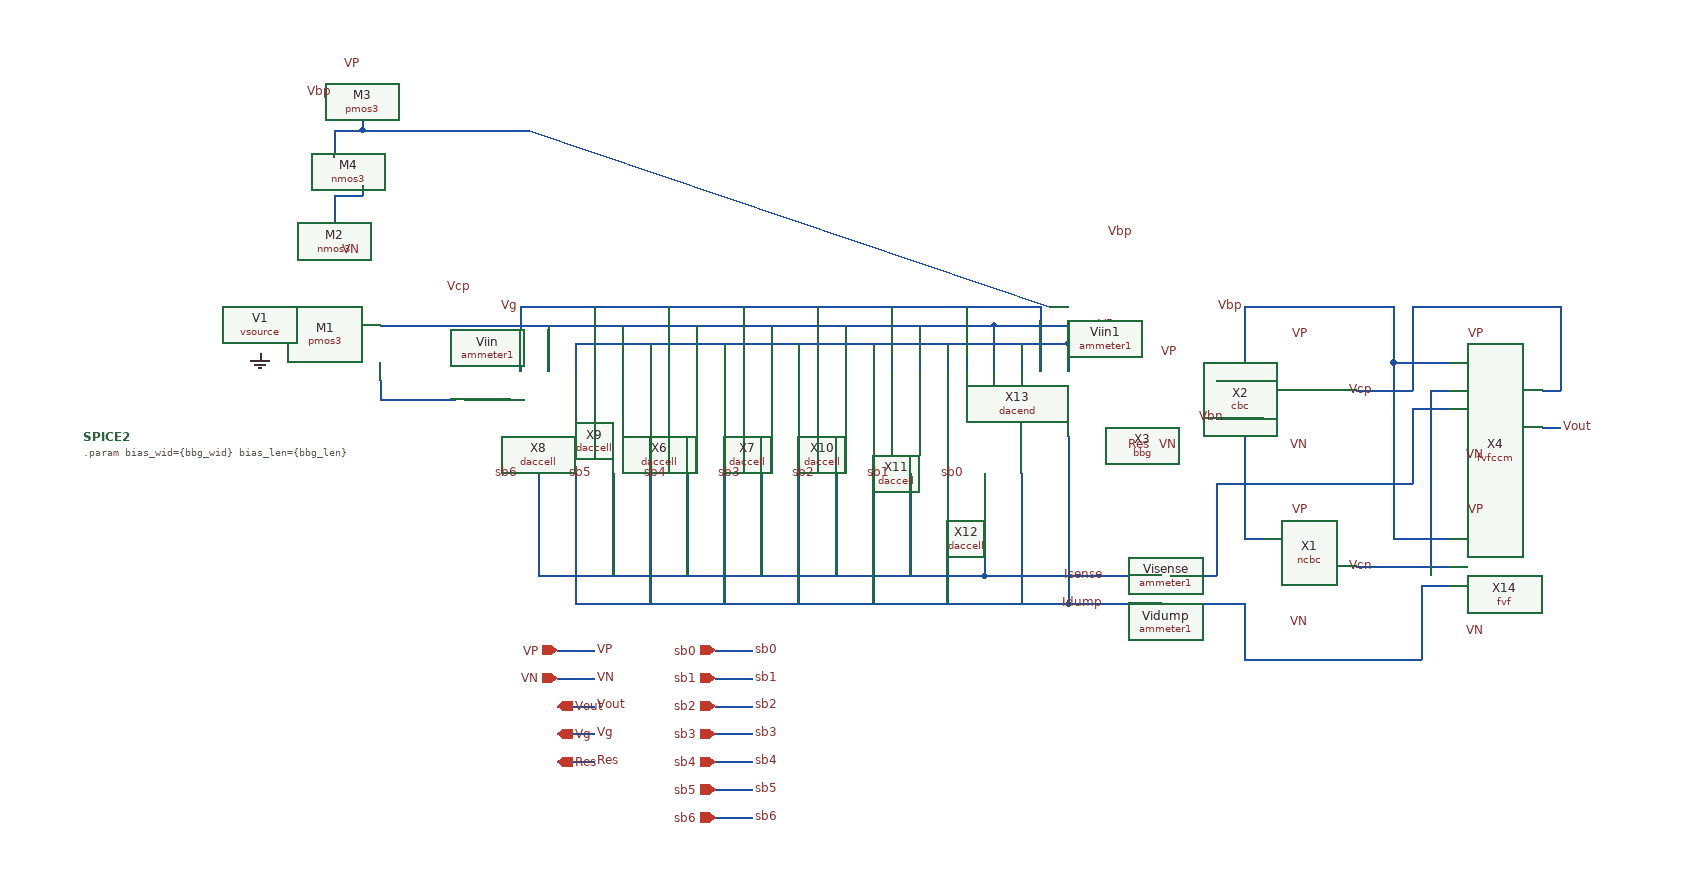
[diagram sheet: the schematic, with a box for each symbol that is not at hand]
v {xschem version=3.4.8RC file_version=1.3}
G {}
K {}
V {}
S {}
F {}
E {}
N 450 -420 600 -420 {lab=Vbp}
N 600 -420 600 -360 {lab=Vbp}
N 600 -360 640 -360 {lab=Vbp}
N 640 -360 650 -360 {lab=Vbp}
N 650 -360 660 -360 {lab=Vbp}
N 760 -290 780 -290 {lab=Vout}
N 220 -420 220 -350 {lab=Vg}
N 140 -420 140 -350 {lab=Vg}
N 60 -420 60 -350 {lab=Vg}
N -20 -420 -20 -350 {lab=Vg}
N -100 -420 -100 -350 {lab=Vg}
N -180 -420 -180 -350 {lab=Vg}
N -260 -420 -260 -350 {lab=Vg}
N -340 -420 -340 -350 {lab=Vg}
N -340 -420 220 -420 {lab=Vg}
N -490 -340 -490 -320 {lab=#net1}
N 160 -240 160 -130 {lab=Isense}
N 200 -240 200 -100 {lab=Idump}
N 80 -240 80 -130 {lab=Isense}
N 120 -240 120 -100 {lab=Idump}
N 0 -240 0 -130 {lab=Isense}
N 40 -240 40 -100 {lab=Idump}
N -80 -240 -80 -130 {lab=Isense}
N -40 -240 -40 -100 {lab=Idump}
N -160 -240 -160 -130 {lab=Isense}
N -120 -240 -120 -100 {lab=Idump}
N -240 -240 -240 -130 {lab=Isense}
N -200 -240 -200 -100 {lab=Idump}
N -320 -240 -320 -130 {lab=Isense}
N -280 -240 -280 -100 {lab=Idump}
N 250 -280 250 -100 {lab=Idump}
N -280 -100 250 -100 {lab=Idump}
N -320 -130 160 -130 {lab=Isense}
N -390 -320 -350 -320 {lab=#net2}
N 250 -100 260 -100 {lab=Idump}
N 160 -130 290 -130 {lab=Isense}
N 440 -170 460 -170 {lab=Vbp}
N 560 -330 580 -330 {lab=Vcp}
N 760 -330 780 -330 {lab=Vcp}
N 640 -330 660 -330 {lab=Vcn}
N -400 -320 -390 -320 {lab=#net2}
N 170 -400 170 -350 {lab=VP}
N 90 -400 90 -350 {lab=VP}
N 10 -400 10 -350 {lab=VP}
N -70 -400 -70 -350 {lab=VP}
N -150 -400 -150 -350 {lab=VP}
N -230 -400 -230 -350 {lab=VP}
N -310 -400 -310 -350 {lab=VP}
N -380 -400 170 -400 {lab=VP}
N -490 -400 -380 -400 {lab=VP}
N -280 -380 -280 -350 {lab=VN}
N -200 -380 -200 -350 {lab=VN}
N -120 -380 -120 -350 {lab=VN}
N -40 -380 -40 -350 {lab=VN}
N 40 -380 40 -350 {lab=VN}
N 120 -380 120 -350 {lab=VN}
N 200 -380 200 -350 {lab=VN}
N 250 -380 250 -350 {lab=VN}
N -280 -380 250 -380 {lab=VN}
N 250 -380 280 -380 {lab=VN}
N 440 -340 440 -170 {lab=Vbp}
N 440 -420 440 -340 {lab=Vbp}
N 440 -420 450 -420 {lab=Vbp}
N 410 -300 460 -300 {lab=Vbn}
N 410 -340 440 -340 {lab=Vbp}
N 600 -170 650 -170 {lab=Vbp}
N 600 -360 600 -170 {lab=Vbp}
N 630 -120 660 -120 {lab=#net3}
N 650 -170 660 -170 {lab=Vbp}
N 780 -420 780 -330 {lab=Vcp}
N 620 -420 780 -420 {lab=Vcp}
N 620 -420 620 -330 {lab=Vcp}
N 580 -330 620 -330 {lab=Vcp}
N 640 -330 640 -140 {lab=Vcn}
N 620 -310 660 -310 {lab=#net4}
N 440 -100 440 -40 {lab=#net3}
N 440 -40 630 -40 {lab=#net3}
N 630 -120 630 -40 {lab=#net3}
N 620 -310 620 -230 {lab=#net4}
N 410 -230 620 -230 {lab=#net4}
N 410 -230 410 -130 {lab=#net4}
N 170 -400 280 -400 {lab=VP}
N -130 -50 -90 -50 {lab=sb0}
N -300 10 -260 10 {lab=Vout}
N -270 -20 -260 -20 {lab=VN}
N -300 -20 -270 -20 {lab=VN}
N -300 -50 -260 -50 {lab=VP}
N -300 40 -260 40 {lab=Vg}
N -130 -20 -90 -20 {lab=sb1}
N -130 10 -90 10 {lab=sb2}
N -130 40 -90 40 {lab=sb3}
N -130 70 -90 70 {lab=sb4}
N -130 100 -90 100 {lab=sb5}
N -130 130 -90 130 {lab=sb6}
N -300 70 -260 70 {lab=Res}
N 580 -140 660 -140 {lab=Vcn}
N 560 -140 580 -140 {lab=Vcn}
N 290 -130 350 -130 {lab=Isense}
N 360 -130 410 -130 {lab=#net4}
N 260 -100 350 -100 {lab=Idump}
N 360 -100 440 -100 {lab=#net3}
N -490 -320 -410 -320 {lab=#net1}
N -540 -610 -540 -580 {lab=#net5}
N -540 -610 -510 -610 {lab=#net5}
N -510 -550 -510 -540 {lab=#net6}
N -510 -620 -510 -610 {lab=#net5}
N -510 -610 -330 -610 {lab=#net5}
N -330 -610 230 -420 {lab=#net5}
N -540 -540 -540 -510 {lab=#net6}
N -540 -540 -510 -540 {lab=#net6}
C {cbc.sym} 460 -270 0 0 {name=X2}
C {bbg.sym} 330 -270 0 0 {name=X3}
C {fvfccm.sym} 670 -260 0 0 {name=X4}
C {lab_pin.sym} 580 -330 1 0 {name=p3 sig_type=std_logic lab=Vcp}
C {lab_pin.sym} 420 -300 3 0 {name=p5 sig_type=std_logic lab=Vbn}
C {daccell.sym} -190 -240 0 0 {name=X6}
C {daccell.sym} -110 -240 0 0 {name=X7}
C {daccell.sym} -350 -240 0 0 {name=X8}
C {daccell.sym} -270 -240 0 0 {name=X9}
C {daccell.sym} -30 -240 0 0 {name=X10}
C {daccell.sym} 50 -240 0 0 {name=X11}
C {daccell.sym} 130 -240 0 0 {name=X12}
C {dacend.sym} 210 -280 0 0 {name=X13}
C {lab_pin.sym} -520 -370 0 0 {name=p20 sig_type=std_logic lab=Vbp}
C {fvf.sym} 660 -70 0 0 {name=X14}
C {lab_pin.sym} 290 -130 1 0 {name=p9 sig_type=std_logic lab=Isense}
C {lab_pin.sym} 140 -240 1 1 {name=p17 sig_type=std_logic lab=sb0}
C {lab_pin.sym} 60 -240 1 1 {name=p18 sig_type=std_logic lab=sb1}
C {lab_pin.sym} -20 -240 1 1 {name=p19 sig_type=std_logic lab=sb2}
C {lab_pin.sym} -100 -240 1 1 {name=p21 sig_type=std_logic lab=sb3}
C {lab_pin.sym} -180 -240 1 1 {name=p22 sig_type=std_logic lab=sb4}
C {lab_pin.sym} -260 -240 1 1 {name=p23 sig_type=std_logic lab=sb5}
C {lab_pin.sym} -340 -240 1 1 {name=p24 sig_type=std_logic lab=sb6}
C {lab_pin.sym} 290 -100 3 0 {name=p25 sig_type=std_logic lab=Idump}
C {madvlsi/pmos3.sym} -490 -370 0 0 {name=M1
L=\{bias_len\}
W=\{bias_wid\}
body=VP
nf=1
mult=1/3
ad="'int((nf+1)/2) * W/nf * 0.29'" 
pd="'2*int((nf+1)/2) * (W/nf + 0.29)'"
as="'int((nf+2)/2) * W/nf * 0.29'" 
ps="'2*int((nf+2)/2) * (W/nf + 0.29)'"
nrd="'0.29 / W'" nrs="'0.29 / W'"
sa=0 sb=0 sd=0
model=pfet_01v8
spiceprefix=X
}
C {code_shown.sym} -810 -280 0 0 {name=SPICE2 only_toplevel=false value="
.param bias_wid=\{bbg_wid\} bias_len=\{bbg_len\}
"}
C {ncbc.sym} 460 -80 0 0 {name=X1}
C {lab_pin.sym} 440 -420 0 0 {name=p26 sig_type=std_logic lab=Vbp}
C {lab_pin.sym} 280 -400 2 0 {name=p2 sig_type=std_logic lab=VP}
C {lab_pin.sym} 280 -380 2 0 {name=p10 sig_type=std_logic lab=VN}
C {lab_pin.sym} 370 -370 1 0 {name=p4 sig_type=std_logic lab=VP}
C {lab_pin.sym} 370 -270 3 0 {name=p7 sig_type=std_logic lab=VN}
C {lab_pin.sym} 510 -80 3 0 {name=p11 sig_type=std_logic lab=VN}
C {lab_pin.sym} 700 -70 3 0 {name=p12 sig_type=std_logic lab=VN}
C {lab_pin.sym} 700 -260 3 0 {name=p13 sig_type=std_logic lab=VN}
C {lab_pin.sym} 510 -270 3 0 {name=p14 sig_type=std_logic lab=VN}
C {lab_pin.sym} 510 -200 1 0 {name=p15 sig_type=std_logic lab=VP}
C {lab_pin.sym} 700 -200 1 0 {name=p16 sig_type=std_logic lab=VP}
C {lab_pin.sym} 700 -390 1 0 {name=p30 sig_type=std_logic lab=VP}
C {lab_pin.sym} 510 -390 1 0 {name=p31 sig_type=std_logic lab=VP}
C {lab_pin.sym} 780 -290 2 0 {name=p1 sig_type=std_logic lab=Vout}
C {lab_pin.sym} -90 -50 2 0 {name=p8 sig_type=std_logic lab=sb0}
C {lab_pin.sym} -260 -20 2 0 {name=p27 sig_type=std_logic lab=VN
}
C {lab_pin.sym} -260 -50 2 0 {name=p28 sig_type=std_logic lab=VP
}
C {lab_pin.sym} -260 10 2 0 {name=p32 sig_type=std_logic lab=Vout
}
C {iopin.sym} -300 -50 2 0 {name=p33 lab=VP}
C {iopin.sym} -300 -20 2 0 {name=p34 lab=VN}
C {opin.sym} -300 10 2 0 {name=p35 lab=Vout}
C {ipin.sym} -130 -50 0 0 {name=p36 lab=sb0}
C {lab_pin.sym} -260 40 2 0 {name=p37 sig_type=std_logic lab=Vg
}
C {opin.sym} -300 40 2 0 {name=p38 lab=Vg}
C {ipin.sym} -130 -20 0 0 {name=p40 lab=sb1}
C {ipin.sym} -130 10 0 0 {name=p42 lab=sb2}
C {ipin.sym} -130 40 0 0 {name=p44 lab=sb3}
C {ipin.sym} -130 70 0 0 {name=p46 lab=sb4}
C {ipin.sym} -130 100 0 0 {name=p48 lab=sb5}
C {ipin.sym} -130 130 0 0 {name=p50 lab=sb6}
C {lab_pin.sym} -90 -20 0 1 {name=p39 sig_type=std_logic lab=sb1}
C {lab_pin.sym} -90 10 0 1 {name=p41 sig_type=std_logic lab=sb2}
C {lab_pin.sym} -90 40 0 1 {name=p43 sig_type=std_logic lab=sb3}
C {lab_pin.sym} -90 70 0 1 {name=p45 sig_type=std_logic lab=sb4}
C {lab_pin.sym} -90 100 0 1 {name=p47 sig_type=std_logic lab=sb5}
C {lab_pin.sym} -90 130 0 1 {name=p49 sig_type=std_logic lab=sb6}
C {lab_pin.sym} 340 -270 3 0 {name=p51 sig_type=std_logic lab=Res}
C {lab_pin.sym} -260 70 2 0 {name=p52 sig_type=std_logic lab=Res
}
C {opin.sym} -300 70 2 0 {name=p53 lab=Res}
C {lab_pin.sym} 580 -140 1 0 {name=p6 sig_type=std_logic lab=Vcn}
C {lab_pin.sym} -390 -440 0 0 {name=p29 sig_type=std_logic lab=Vcp}
C {lab_pin.sym} 290 -500 2 0 {name=p54 sig_type=std_logic lab=Vbp}
C {madvlsi/ammeter1.sym} 350 -130 3 0 {name=Visense}
C {madvlsi/ammeter1.sym} 350 -100 3 0 {name=Vidump}
C {madvlsi/ammeter1.sym} -410 -320 3 0 {name=Viin}
C {lab_pin.sym} -340 -420 0 0 {name=p55 sig_type=std_logic lab=Vg}
C {madvlsi/vsource.sym} -620 -400 0 0 {name=V1
value=1}
C {madvlsi/gnd.sym} -620 -370 0 0 {name=l6 lab=GND}
C {madvlsi/nmos3.sym} -510 -510 0 0 {name=M2
L=\{bias_len\}
W=\{bias_wid\}
body=VN
nf=1
mult=1
ad="'int((nf+1)/2) * W/nf * 0.29'" 
pd="'2*int((nf+1)/2) * (W/nf + 0.29)'"
as="'int((nf+2)/2) * W/nf * 0.29'" 
ps="'2*int((nf+2)/2) * (W/nf + 0.29)'"
nrd="'0.29 / W'" nrs="'0.29 / W'"
sa=0 sb=0 sd=0
model=nfet_01v8
spiceprefix=X
}
C {lab_pin.sym} -510 -480 3 0 {name=p57 sig_type=std_logic lab=VN}
C {madvlsi/pmos3.sym} -510 -650 0 0 {name=M3
L=\{bias_len\}*3
W=\{bias_wid\}/3
body=VP
nf=1
mult=1
ad="'int((nf+1)/2) * W/nf * 0.29'" 
pd="'2*int((nf+1)/2) * (W/nf + 0.29)'"
as="'int((nf+2)/2) * W/nf * 0.29'" 
ps="'2*int((nf+2)/2) * (W/nf + 0.29)'"
nrd="'0.29 / W'" nrs="'0.29 / W'"
sa=0 sb=0 sd=0
model=pfet_01v8
spiceprefix=X
}
C {madvlsi/nmos3.sym} -510 -580 0 0 {name=M4
L=\{bias_len\}
W=\{bias_wid\}
body=VN
nf=1
mult=1
ad="'int((nf+1)/2) * W/nf * 0.29'" 
pd="'2*int((nf+1)/2) * (W/nf + 0.29)'"
as="'int((nf+2)/2) * W/nf * 0.29'" 
ps="'2*int((nf+2)/2) * (W/nf + 0.29)'"
nrd="'0.29 / W'" nrs="'0.29 / W'"
sa=0 sb=0 sd=0
model=nfet_01v8
spiceprefix=X
}
C {lab_pin.sym} -510 -680 1 0 {name=p59 sig_type=std_logic lab=VP}
C {madvlsi/ammeter1.sym} 220 -420 3 0 {name=Viin1}
C {lab_pin.sym} -540 -650 0 0 {name=p56 sig_type=std_logic lab=Vbp}
